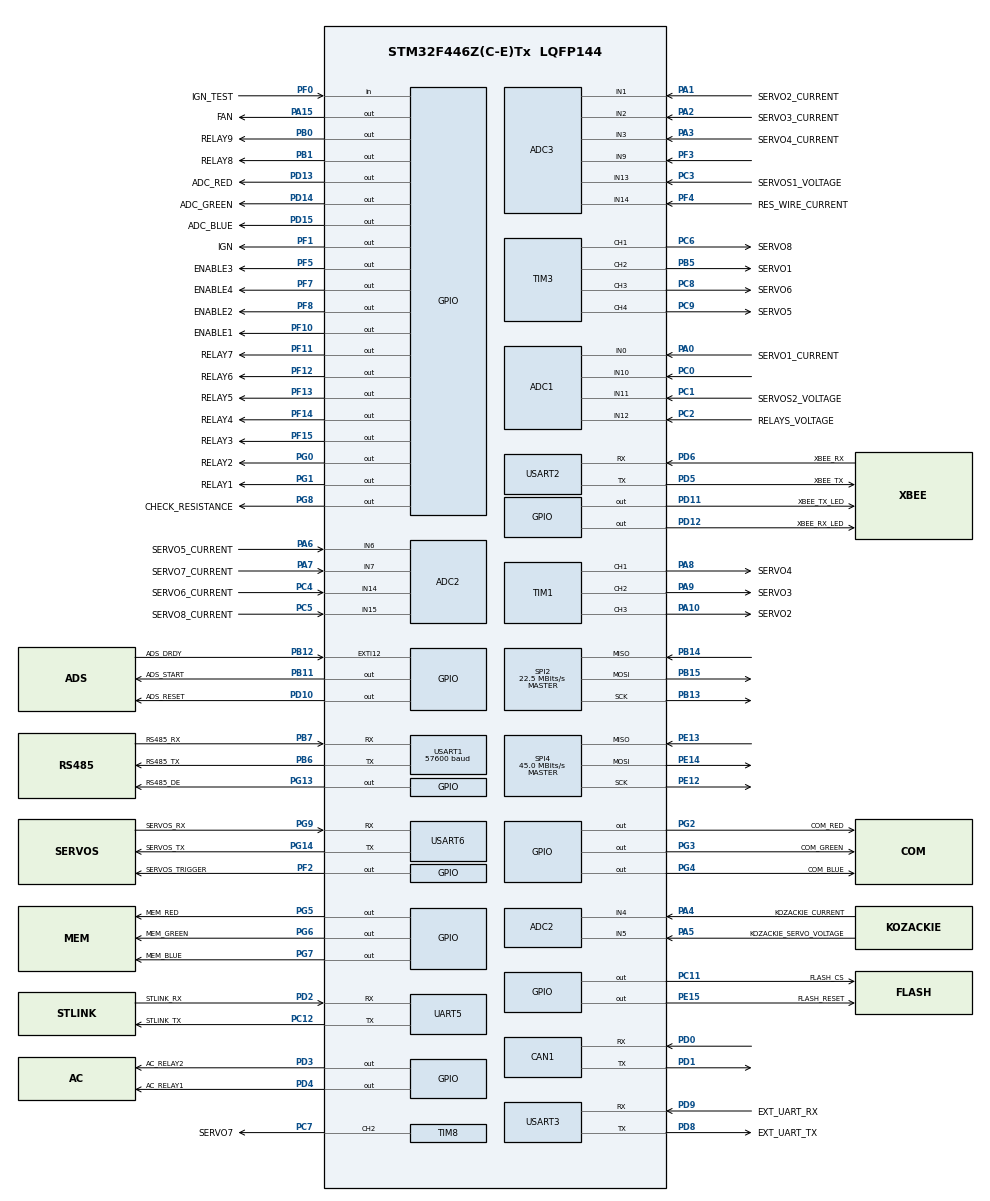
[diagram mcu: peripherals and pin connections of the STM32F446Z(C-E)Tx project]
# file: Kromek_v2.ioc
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ADC1.Channel-0\#ChannelRegularConversion=ADC_CHANNEL_VREFINT
ADC1.Channel-1\#ChannelRegularConversion=ADC_CHANNEL_10
ADC1.Channel-14\#ChannelRegularConversion=ADC_CHANNEL_12
ADC1.Channel-15\#ChannelRegularConversion=ADC_CHANNEL_0
ADC1.Channel-16\#ChannelRegularConversion=ADC_CHANNEL_TEMPSENSOR
ADC1.Channel-2\#ChannelRegularConversion=ADC_CHANNEL_11
ADC1.ClockPrescaler=ADC_CLOCK_SYNC_PCLK_DIV8
ADC1.ContinuousConvMode=ENABLE
ADC1.DMAContinuousRequests=ENABLE
ADC1.DiscontinuousConvMode=DISABLE
ADC1.EOCSelection=ADC_EOC_SEQ_CONV
ADC1.ExternalTrigConv=ADC_SOFTWARE_START
ADC1.InjNumberOfConversion=0
ADC1.NbrOfConversion=6
ADC1.NbrOfConversionFlag=1
ADC1.Rank-0\#ChannelRegularConversion=1
ADC1.Rank-1\#ChannelRegularConversion=2
ADC1.Rank-14\#ChannelRegularConversion=4
ADC1.Rank-15\#ChannelRegularConversion=5
ADC1.Rank-16\#ChannelRegularConversion=6
ADC1.Rank-2\#ChannelRegularConversion=3
ADC1.SamplingTime-0\#ChannelRegularConversion=ADC_SAMPLETIME_480CYCLES
ADC1.SamplingTime-1\#ChannelRegularConversion=ADC_SAMPLETIME_480CYCLES
ADC1.SamplingTime-14\#ChannelRegularConversion=ADC_SAMPLETIME_480CYCLES
ADC1.SamplingTime-15\#ChannelRegularConversion=ADC_SAMPLETIME_480CYCLES
ADC1.SamplingTime-16\#ChannelRegularConversion=ADC_SAMPLETIME_480CYCLES
ADC1.SamplingTime-2\#ChannelRegularConversion=ADC_SAMPLETIME_480CYCLES
ADC1.ScanConvMode=ENABLE
ADC1.master=1
ADC2.Channel-1\#ChannelRegularConversion=ADC_CHANNEL_4
ADC2.Channel-2\#ChannelRegularConversion=ADC_CHANNEL_5
ADC2.Channel-3\#ChannelRegularConversion=ADC_CHANNEL_6
ADC2.Channel-4\#ChannelRegularConversion=ADC_CHANNEL_7
ADC2.Channel-5\#ChannelRegularConversion=ADC_CHANNEL_14
ADC2.Channel-6\#ChannelRegularConversion=ADC_CHANNEL_15
ADC2.ClockPrescaler=ADC_CLOCK_SYNC_PCLK_DIV8
ADC2.ContinuousConvMode=ENABLE
ADC2.DMAContinuousRequests=ENABLE
ADC2.EOCSelection=ADC_EOC_SEQ_CONV
ADC2.NbrOfConversion=6
ADC2.NbrOfConversionFlag=1
ADC2.Rank-1\#ChannelRegularConversion=1
ADC2.Rank-2\#ChannelRegularConversion=2
ADC2.Rank-3\#ChannelRegularConversion=3
ADC2.Rank-4\#ChannelRegularConversion=4
ADC2.Rank-5\#ChannelRegularConversion=5
ADC2.Rank-6\#ChannelRegularConversion=6
ADC2.SamplingTime-1\#ChannelRegularConversion=ADC_SAMPLETIME_480CYCLES
ADC2.SamplingTime-2\#ChannelRegularConversion=ADC_SAMPLETIME_480CYCLES
ADC2.SamplingTime-3\#ChannelRegularConversion=ADC_SAMPLETIME_480CYCLES
ADC2.SamplingTime-4\#ChannelRegularConversion=ADC_SAMPLETIME_480CYCLES
ADC2.SamplingTime-5\#ChannelRegularConversion=ADC_SAMPLETIME_480CYCLES
ADC2.SamplingTime-6\#ChannelRegularConversion=ADC_SAMPLETIME_480CYCLES
ADC2.ScanConvMode=ENABLE
ADC3.Channel-1\#ChannelRegularConversion=ADC_CHANNEL_1
ADC3.Channel-2\#ChannelRegularConversion=ADC_CHANNEL_2
ADC3.Channel-3\#ChannelRegularConversion=ADC_CHANNEL_3
ADC3.Channel-4\#ChannelRegularConversion=ADC_CHANNEL_9
ADC3.Channel-5\#ChannelRegularConversion=ADC_CHANNEL_13
ADC3.Channel-7\#ChannelRegularConversion=ADC_CHANNEL_14
ADC3.ClockPrescaler=ADC_CLOCK_SYNC_PCLK_DIV8
ADC3.ContinuousConvMode=ENABLE
ADC3.DMAContinuousRequests=ENABLE
ADC3.EOCSelection=ADC_EOC_SEQ_CONV
ADC3.NbrOfConversion=6
ADC3.NbrOfConversionFlag=1
ADC3.Rank-1\#ChannelRegularConversion=1
ADC3.Rank-2\#ChannelRegularConversion=2
ADC3.Rank-3\#ChannelRegularConversion=3
ADC3.Rank-4\#ChannelRegularConversion=4
ADC3.Rank-5\#ChannelRegularConversion=5
ADC3.Rank-7\#ChannelRegularConversion=6
ADC3.SamplingTime-1\#ChannelRegularConversion=ADC_SAMPLETIME_480CYCLES
ADC3.SamplingTime-2\#ChannelRegularConversion=ADC_SAMPLETIME_480CYCLES
ADC3.SamplingTime-3\#ChannelRegularConversion=ADC_SAMPLETIME_480CYCLES
ADC3.SamplingTime-4\#ChannelRegularConversion=ADC_SAMPLETIME_480CYCLES
ADC3.SamplingTime-5\#ChannelRegularConversion=ADC_SAMPLETIME_480CYCLES
ADC3.SamplingTime-7\#ChannelRegularConversion=ADC_SAMPLETIME_480CYCLES
ADC3.ScanConvMode=ENABLE
CAN1.BS1=CAN_BS1_1TQ
CAN1.BS2=CAN_BS2_1TQ
CAN1.CalculateTimeQuantum=355.55555555555554
Dma.ADC1.0.Direction=DMA_PERIPH_TO_MEMORY
Dma.ADC1.0.FIFOMode=DMA_FIFOMODE_DISABLE
Dma.ADC1.0.Instance=DMA2_Stream4
Dma.ADC1.0.MemDataAlignment=DMA_MDATAALIGN_HALFWORD
Dma.ADC1.0.MemInc=DMA_MINC_ENABLE
Dma.ADC1.0.Mode=DMA_CIRCULAR
Dma.ADC1.0.PeriphDataAlignment=DMA_PDATAALIGN_HALFWORD
Dma.ADC1.0.PeriphInc=DMA_PINC_DISABLE
Dma.ADC1.0.Priority=DMA_PRIORITY_LOW
Dma.ADC2.1.Direction=DMA_PERIPH_TO_MEMORY
Dma.ADC2.1.FIFOMode=DMA_FIFOMODE_DISABLE
Dma.ADC2.1.Instance=DMA2_Stream2
Dma.ADC2.1.MemDataAlignment=DMA_MDATAALIGN_HALFWORD
Dma.ADC2.1.MemInc=DMA_MINC_ENABLE
Dma.ADC2.1.Mode=DMA_CIRCULAR
Dma.ADC2.1.PeriphDataAlignment=DMA_PDATAALIGN_HALFWORD
Dma.ADC2.1.PeriphInc=DMA_PINC_DISABLE
Dma.ADC2.1.Priority=DMA_PRIORITY_LOW
Dma.ADC3.2.Direction=DMA_PERIPH_TO_MEMORY
Dma.ADC3.2.FIFOMode=DMA_FIFOMODE_DISABLE
Dma.ADC3.2.Instance=DMA2_Stream0
Dma.ADC3.2.MemDataAlignment=DMA_MDATAALIGN_HALFWORD
Dma.ADC3.2.MemInc=DMA_MINC_ENABLE
Dma.ADC3.2.Mode=DMA_CIRCULAR
Dma.ADC3.2.PeriphDataAlignment=DMA_PDATAALIGN_HALFWORD
Dma.ADC3.2.PeriphInc=DMA_PINC_DISABLE
Dma.ADC3.2.Priority=DMA_PRIORITY_LOW
Dma.Request0=ADC1
Dma.Request1=ADC2
Dma.Request10=USART2_TX
Dma.Request2=ADC3
Dma.Request3=SPI2_RX
Dma.Request4=SPI2_TX
Dma.Request5=SPI4_RX
Dma.Request6=SPI4_TX
Dma.Request7=USART1_RX
Dma.Request8=USART1_TX
Dma.Request9=USART2_RX
Dma.SPI2_RX.3.Direction=DMA_PERIPH_TO_MEMORY
Dma.SPI2_RX.3.FIFOMode=DMA_FIFOMODE_DISABLE
Dma.SPI2_RX.3.Instance=DMA1_Stream3
Dma.SPI2_RX.3.MemDataAlignment=DMA_MDATAALIGN_BYTE
Dma.SPI2_RX.3.MemInc=DMA_MINC_ENABLE
Dma.SPI2_RX.3.Mode=DMA_NORMAL
Dma.SPI2_RX.3.PeriphDataAlignment=DMA_PDATAALIGN_BYTE
Dma.SPI2_RX.3.PeriphInc=DMA_PINC_DISABLE
Dma.SPI2_RX.3.Priority=DMA_PRIORITY_LOW
Dma.SPI2_TX.4.Direction=DMA_MEMORY_TO_PERIPH
Dma.SPI2_TX.4.FIFOMode=DMA_FIFOMODE_DISABLE
Dma.SPI2_TX.4.Instance=DMA1_Stream4
Dma.SPI2_TX.4.MemDataAlignment=DMA_MDATAALIGN_BYTE
Dma.SPI2_TX.4.MemInc=DMA_MINC_ENABLE
Dma.SPI2_TX.4.Mode=DMA_NORMAL
Dma.SPI2_TX.4.PeriphDataAlignment=DMA_PDATAALIGN_BYTE
Dma.SPI2_TX.4.PeriphInc=DMA_PINC_DISABLE
Dma.SPI2_TX.4.Priority=DMA_PRIORITY_LOW
Dma.SPI4_RX.5.Direction=DMA_PERIPH_TO_MEMORY
Dma.SPI4_RX.5.FIFOMode=DMA_FIFOMODE_DISABLE
Dma.SPI4_RX.5.Instance=DMA2_Stream3
Dma.SPI4_RX.5.MemDataAlignment=DMA_MDATAALIGN_BYTE
Dma.SPI4_RX.5.MemInc=DMA_MINC_ENABLE
Dma.SPI4_RX.5.Mode=DMA_NORMAL
Dma.SPI4_RX.5.PeriphDataAlignment=DMA_PDATAALIGN_BYTE
Dma.SPI4_RX.5.PeriphInc=DMA_PINC_DISABLE
Dma.SPI4_RX.5.Priority=DMA_PRIORITY_LOW
Dma.SPI4_TX.6.Direction=DMA_MEMORY_TO_PERIPH
Dma.SPI4_TX.6.FIFOMode=DMA_FIFOMODE_DISABLE
Dma.SPI4_TX.6.Instance=DMA2_Stream1
Dma.SPI4_TX.6.MemDataAlignment=DMA_MDATAALIGN_BYTE
Dma.SPI4_TX.6.MemInc=DMA_MINC_ENABLE
Dma.SPI4_TX.6.Mode=DMA_NORMAL
Dma.SPI4_TX.6.PeriphDataAlignment=DMA_PDATAALIGN_BYTE
Dma.SPI4_TX.6.PeriphInc=DMA_PINC_DISABLE
Dma.SPI4_TX.6.Priority=DMA_PRIORITY_LOW
Dma.USART1_RX.7.Direction=DMA_PERIPH_TO_MEMORY
Dma.USART1_RX.7.FIFOMode=DMA_FIFOMODE_DISABLE
Dma.USART1_RX.7.Instance=DMA2_Stream5
Dma.USART1_RX.7.MemDataAlignment=DMA_MDATAALIGN_BYTE
Dma.USART1_RX.7.MemInc=DMA_MINC_ENABLE
Dma.USART1_RX.7.Mode=DMA_NORMAL
Dma.USART1_RX.7.PeriphDataAlignment=DMA_PDATAALIGN_BYTE
Dma.USART1_RX.7.PeriphInc=DMA_PINC_DISABLE
Dma.USART1_RX.7.Priority=DMA_PRIORITY_LOW
Dma.USART1_TX.8.Direction=DMA_MEMORY_TO_PERIPH
Dma.USART1_TX.8.FIFOMode=DMA_FIFOMODE_DISABLE
Dma.USART1_TX.8.Instance=DMA2_Stream7
Dma.USART1_TX.8.MemDataAlignment=DMA_MDATAALIGN_BYTE
Dma.USART1_TX.8.MemInc=DMA_MINC_ENABLE
Dma.USART1_TX.8.Mode=DMA_NORMAL
Dma.USART1_TX.8.PeriphDataAlignment=DMA_PDATAALIGN_BYTE
Dma.USART1_TX.8.PeriphInc=DMA_PINC_DISABLE
Dma.USART1_TX.8.Priority=DMA_PRIORITY_LOW
Dma.USART2_RX.9.Direction=DMA_PERIPH_TO_MEMORY
Dma.USART2_RX.9.FIFOMode=DMA_FIFOMODE_DISABLE
Dma.USART2_RX.9.Instance=DMA1_Stream5
Dma.USART2_RX.9.MemDataAlignment=DMA_MDATAALIGN_BYTE
Dma.USART2_RX.9.MemInc=DMA_MINC_ENABLE
Dma.USART2_RX.9.Mode=DMA_NORMAL
Dma.USART2_RX.9.PeriphDataAlignment=DMA_PDATAALIGN_BYTE
Dma.USART2_RX.9.PeriphInc=DMA_PINC_DISABLE
Dma.USART2_RX.9.Priority=DMA_PRIORITY_LOW
Dma.USART2_TX.10.Direction=DMA_MEMORY_TO_PERIPH
Dma.USART2_TX.10.FIFOMode=DMA_FIFOMODE_DISABLE
Dma.USART2_TX.10.Instance=DMA1_Stream6
Dma.USART2_TX.10.MemDataAlignment=DMA_MDATAALIGN_BYTE
Dma.USART2_TX.10.MemInc=DMA_MINC_ENABLE
Dma.USART2_TX.10.Mode=DMA_NORMAL
Dma.USART2_TX.10.PeriphDataAlignment=DMA_PDATAALIGN_BYTE
Dma.USART2_TX.10.PeriphInc=DMA_PINC_DISABLE
Dma.USART2_TX.10.Priority=DMA_PRIORITY_LOW
Mcu.Family=STM32F4
Mcu.Name=STM32F446Z(C-E)Tx
Mcu.Package=LQFP144
NVIC.ADC_IRQn=true\:0\:0\:false\:false\:true\:true\:true
NVIC.DMA1_Stream3_IRQn=true\:0\:0\:false\:false\:true\:false\:true
NVIC.DMA1_Stream4_IRQn=true\:0\:0\:false\:false\:true\:false\:true
NVIC.DMA1_Stream5_IRQn=true\:0\:0\:false\:false\:true\:false\:true
NVIC.DMA1_Stream6_IRQn=true\:0\:0\:false\:false\:true\:false\:true
NVIC.DMA2_Stream0_IRQn=true\:0\:0\:false\:false\:true\:false\:true
NVIC.DMA2_Stream1_IRQn=true\:0\:0\:false\:false\:true\:false\:true
NVIC.DMA2_Stream2_IRQn=true\:0\:0\:false\:false\:true\:false\:true
NVIC.DMA2_Stream3_IRQn=true\:0\:0\:false\:false\:true\:false\:true
NVIC.DMA2_Stream4_IRQn=true\:0\:0\:false\:false\:true\:false\:true
NVIC.DMA2_Stream5_IRQn=true\:0\:0\:true\:false\:true\:false\:true
NVIC.DMA2_Stream7_IRQn=true\:0\:0\:true\:false\:true\:false\:true
NVIC.EXTI15_10_IRQn=true\:0\:0\:false\:false\:true\:true\:true
NVIC.PriorityGroup=NVIC_PRIORITYGROUP_4
NVIC.SPI2_IRQn=true\:0\:0\:false\:false\:true\:true\:true
NVIC.SPI4_IRQn=true\:0\:0\:false\:false\:true\:true\:true
NVIC.TIM8_TRG_COM_TIM14_IRQn=true\:1\:0\:true\:false\:true\:true\:true
NVIC.TIM8_UP_TIM13_IRQn=true\:2\:0\:true\:false\:true\:true\:true
NVIC.USART1_IRQn=true\:0\:0\:true\:false\:true\:true\:true
NVIC.USART2_IRQn=true\:0\:0\:false\:false\:true\:true\:true
NVIC.USART3_IRQn=true\:0\:0\:false\:false\:true\:true\:true
PA0-WKUP.GPIO_Label=SERVO1_CURRENT
PA0-WKUP.Signal=ADCx_IN0
PA1.GPIO_Label=SERVO2_CURRENT
PA1.Signal=ADCx_IN1
PA10.GPIO_Label=SERVO2
PA10.Signal=S_TIM1_CH3
PA13.Mode=Serial_Wire
PA13.Signal=SYS_JTMS-SWDIO
PA14.Mode=Serial_Wire
PA14.Signal=SYS_JTCK-SWCLK
PA15.GPIO_Label=FAN
PA15.Signal=GPIO_Output
PA2.GPIO_Label=SERVO3_CURRENT
PA2.Signal=ADCx_IN2
PA3.GPIO_Label=SERVO4_CURRENT
PA3.Signal=ADCx_IN3
PA4.GPIO_Label=KOZACKIE_CURRENT
PA4.Signal=ADCx_IN4
PA5.GPIO_Label=KOZACKIE_SERVO_VOLTAGE
PA5.Signal=ADCx_IN5
PA6.GPIO_Label=SERVO5_CURRENT
PA6.Signal=ADCx_IN6
PA7.GPIO_Label=SERVO7_CURRENT
PA7.Signal=ADCx_IN7
PA8.GPIO_Label=SERVO4
PA8.Signal=S_TIM1_CH1
PA9.GPIO_Label=SERVO3
PA9.Signal=S_TIM1_CH2
PB0.GPIO_Label=RELAY9
PB0.Signal=GPIO_Output
PB1.GPIO_Label=RELAY8
PB1.Signal=GPIO_Output
PB11.GPIO_Label=ADS_START
PB11.Signal=GPIO_Output
PB12.GPIO_Label=ADS_DRDY
PB12.Signal=GPXTI12
PB13.Mode=Full_Duplex_Master
PB13.Signal=SPI2_SCK
PB14.Mode=Full_Duplex_Master
PB14.Signal=SPI2_MISO
PB15.Mode=Full_Duplex_Master
PB15.Signal=SPI2_MOSI
PB2.Signal=QUADSPI_CLK
PB3.Signal=I2C2_SDA
PB4.Signal=I2C3_SDA
PB5.GPIO_Label=SERVO1
PB5.Signal=S_TIM3_CH2
PB6.GPIO_Label=RS485_TX
PB6.Mode=Asynchronous
PB6.Signal=USART1_TX
PB7.GPIO_Label=RS485_RX
PB7.Mode=Asynchronous
PB7.Signal=USART1_RX
PB8.Signal=I2C1_SCL
PB9.Signal=I2C1_SDA
PC0.Signal=ADCx_IN10
PC1.GPIO_Label=SERVOS2_VOLTAGE
PC1.Signal=ADCx_IN11
PC11.GPIO_Label=FLASH_CS
PC11.Signal=GPIO_Output
PC12.GPIO_Label=STLINK_TX
PC12.Mode=Asynchronous
PC12.Signal=UART5_TX
PC15-OSC32_OUT.Signal=RCC_OSC32_OUT
PC2.GPIO_Label=RELAYS_VOLTAGE
PC2.Signal=ADCx_IN12
PC3.GPIO_Label=SERVOS1_VOLTAGE
PC3.Signal=ADCx_IN13
PC4.GPIO_Label=SERVO6_CURRENT
PC4.Signal=ADCx_IN14
PC5.GPIO_Label=SERVO8_CURRENT
PC5.Signal=ADCx_IN15
PC6.GPIO_Label=SERVO8
PC6.Signal=S_TIM3_CH1
PC7.GPIO_Label=SERVO7
PC7.Signal=S_TIM8_CH2
PC8.GPIO_Label=SERVO6
PC8.Signal=S_TIM3_CH3
PC9.GPIO_Label=SERVO5
PC9.Signal=S_TIM3_CH4
PD0.Mode=Master
PD0.Signal=CAN1_RX
PD1.Mode=Master
PD1.Signal=CAN1_TX
PD10.GPIO_Label=ADS_RESET
PD10.Signal=GPIO_Output
PD11.GPIO_Label=XBEE_TX_LED
PD11.Signal=GPIO_Output
PD12.GPIO_Label=XBEE_RX_LED
PD12.Signal=GPIO_Output
PD13.GPIO_Label=ADC_RED
PD13.Signal=GPIO_Output
PD14.GPIO_Label=ADC_GREEN
PD14.Signal=GPIO_Output
PD15.GPIO_Label=ADC_BLUE
PD15.Signal=GPIO_Output
PD2.GPIO_Label=STLINK_RX
PD2.Mode=Asynchronous
PD2.Signal=UART5_RX
PD3.GPIO_Label=AC_RELAY2
PD3.Signal=GPIO_Output
PD4.GPIO_Label=AC_RELAY1
PD4.Signal=GPIO_Output
PD5.GPIO_Label=XBEE_TX
PD5.Mode=Asynchronous
PD5.Signal=USART2_TX
PD6.GPIO_Label=XBEE_RX
PD6.Mode=Asynchronous
PD6.Signal=USART2_RX
PD8.GPIO_Label=EXT_UART_TX
PD8.Mode=Asynchronous
PD8.Signal=USART3_TX
PD9.GPIO_Label=EXT_UART_RX
PD9.Mode=Asynchronous
PD9.Signal=USART3_RX
PE10.Signal=QUADSPI_BK2_IO3
PE12.Mode=Full_Duplex_Master
PE12.Signal=SPI4_SCK
PE13.Mode=Full_Duplex_Master
PE13.Signal=SPI4_MISO
PE14.Mode=Full_Duplex_Master
PE14.Signal=SPI4_MOSI
PE15.GPIO_Label=FLASH_RESET
PE15.Signal=GPIO_Output
PE7.Signal=QUADSPI_BK2_IO0
PE8.Signal=QUADSPI_BK2_IO1
PE9.Signal=QUADSPI_BK2_IO2
PF0.GPIO_Label=IGN_TEST
PF0.Signal=GPIO_Input
PF1.GPIO_Label=IGN
PF1.Signal=GPIO_Output
PF10.GPIO_Label=ENABLE1
PF10.Signal=GPIO_Output
PF11.GPIO_Label=RELAY7
PF11.Signal=GPIO_Output
PF12.GPIO_Label=RELAY6
PF12.Signal=GPIO_Output
PF13.GPIO_Label=RELAY5
PF13.Signal=GPIO_Output
PF14.GPIO_Label=RELAY4
PF14.Signal=GPIO_Output
PF15.GPIO_Label=RELAY3
PF15.Signal=GPIO_Output
PF2.GPIO_Label=SERVOS_TRIGGER
PF2.Signal=GPIO_Output
PF3.Mode=IN9
PF3.Signal=ADC3_IN9
PF4.GPIO_Label=RES_WIRE_CURRENT
PF4.Mode=IN14
PF4.Signal=ADC3_IN14
PF5.GPIO_Label=ENABLE3
PF5.Signal=GPIO_Output
PF7.GPIO_Label=ENABLE4
PF7.Signal=GPIO_Output
PF8.GPIO_Label=ENABLE2
PF8.Signal=GPIO_Output
PF9.GPIO_Label=BUZZER
PF9.Signal=S_TIM14_CH1
PG0.GPIO_Label=RELAY2
PG0.Signal=GPIO_Output
PG1.GPIO_Label=RELAY1
PG1.Signal=GPIO_Output
PG13.GPIO_Label=RS485_DE
PG13.Signal=GPIO_Output
PG14.GPIO_Label=SERVOS_TX
PG14.Mode=Asynchronous
PG14.Signal=USART6_TX
PG2.GPIO_Label=COM_RED
PG2.Signal=GPIO_Output
PG3.GPIO_Label=COM_GREEN
PG3.Signal=GPIO_Output
PG4.GPIO_Label=COM_BLUE
PG4.Signal=GPIO_Output
PG5.GPIO_Label=MEM_RED
PG5.Signal=GPIO_Output
PG6.GPIO_Label=MEM_GREEN
PG6.Signal=GPIO_Output
PG7.GPIO_Label=MEM_BLUE
PG7.Signal=GPIO_Output
PG8.GPIO_Label=CHECK_RESISTANCE
PG8.Signal=GPIO_Output
PG9.GPIO_Label=SERVOS_RX
PG9.Mode=Asynchronous
PG9.Signal=USART6_RX
PH0-OSC_IN.Signal=RCC_OSC_IN
PH1-OSC_OUT.Signal=RCC_OSC_OUT
ProjectManager.HeapSize=0x200
ProjectManager.StackSize=0x400
ProjectManager.TargetToolchain=SW4STM32
RCC.AHBFreq_Value=180000000
RCC.APB1CLKDivider=RCC_HCLK_DIV4
RCC.APB1Freq_Value=45000000
RCC.APB1TimFreq_Value=90000000
RCC.APB2CLKDivider=RCC_HCLK_DIV2
RCC.APB2Freq_Value=90000000
RCC.APB2TimFreq_Value=180000000
RCC.CortexFreq_Value=180000000
RCC.HCLKFreq_Value=180000000
RCC.HSE_VALUE=8000000
RCC.PLLM=8
RCC.PLLN=180
RCC.PLLQ=8
RCC.PLLSAIM=8
RCC.PLLSAIN=96
RCC.PLLSAIP=RCC_PLLSAIP_DIV4
RCC.SYSCLKFreq_VALUE=180000000
RCC.SYSCLKSource=RCC_SYSCLKSOURCE_PLLRCLK
RCC.USBCLockSelection=RCC_CLK48CLKSOURCE_PLLSAIP
RCC.USBFreq_Value=48000000
RCC.VCOOutputFreq_Value=360000000
SH.ADCx_IN0.0=ADC1_IN0,IN0
SH.ADCx_IN1.0=ADC3_IN1,IN1
SH.ADCx_IN10.0=ADC1_IN10,IN10
SH.ADCx_IN11.0=ADC1_IN11,IN11
SH.ADCx_IN12.0=ADC1_IN12,IN12
SH.ADCx_IN13.0=ADC3_IN13,IN13
SH.ADCx_IN14.0=ADC2_IN14,IN14
SH.ADCx_IN15.0=ADC2_IN15,IN15
SH.ADCx_IN2.0=ADC3_IN2,IN2
SH.ADCx_IN3.0=ADC3_IN3,IN3
SH.ADCx_IN4.0=ADC2_IN4,IN4
SH.ADCx_IN5.0=ADC2_IN5,IN5
SH.ADCx_IN6.0=ADC2_IN6,IN6
SH.ADCx_IN7.0=ADC2_IN7,IN7
SH.S_TIM14_CH1.0=TIM14_CH1
SH.S_TIM1_CH1.0=TIM1_CH1,PWM Generation1 CH1
SH.S_TIM1_CH2.0=TIM1_CH2,PWM Generation2 CH2
SH.S_TIM1_CH3.0=TIM1_CH3,PWM Generation3 CH3
SH.S_TIM3_CH1.0=TIM3_CH1,PWM Generation1 CH1
SH.S_TIM3_CH2.0=TIM3_CH2,PWM Generation2 CH2
SH.S_TIM3_CH3.0=TIM3_CH3,PWM Generation3 CH3
SH.S_TIM3_CH4.0=TIM3_CH4,PWM Generation4 CH4
SH.S_TIM8_CH2.0=TIM8_CH2,PWM Generation2 CH2
SPI2.BaudRatePrescaler=SPI_BAUDRATEPRESCALER_2
SPI2.CalculateBaudRate=22.5 MBits/s
SPI2.Direction=SPI_DIRECTION_2LINES
SPI2.Mode=SPI_MODE_MASTER
SPI2.VirtualType=VM_MASTER
SPI4.CalculateBaudRate=45.0 MBits/s
SPI4.Direction=SPI_DIRECTION_2LINES
SPI4.Mode=SPI_MODE_MASTER
SPI4.VirtualType=VM_MASTER
TIM1.Channel-PWM\ Generation1\ CH1=TIM_CHANNEL_1
TIM1.Channel-PWM\ Generation2\ CH2=TIM_CHANNEL_2
TIM1.Channel-PWM\ Generation3\ CH3=TIM_CHANNEL_3
TIM1.TIM_MasterOutputTrigger=TIM_TRGO_RESET
TIM13.Period=9
TIM13.Prescaler=39
TIM14.Period=9
TIM14.Prescaler=39
TIM3.Channel-PWM\ Generation1\ CH1=TIM_CHANNEL_1
TIM3.Channel-PWM\ Generation2\ CH2=TIM_CHANNEL_2
TIM3.Channel-PWM\ Generation3\ CH3=TIM_CHANNEL_3
TIM3.Channel-PWM\ Generation4\ CH4=TIM_CHANNEL_4
TIM8.Channel-PWM\ Generation2\ CH2=TIM_CHANNEL_2
TIM8.Period=0
TIM8.Prescaler=0
TIM8.TIM_MasterOutputTrigger=TIM_TRGO_UPDATE
UART5.VirtualMode=Asynchronous
USART1.BaudRate=57600
USART1.VirtualMode=VM_ASYNC
USART2.VirtualMode=VM_ASYNC
USART3.VirtualMode=VM_ASYNC
USART6.VirtualMode=VM_ASYNC
VP_ADC1_TempSens_Input.Mode=IN-TempSens
VP_ADC1_Vref_Input.Mode=IN-Vrefint
VP_CRC_VS_CRC.Mode=CRC_Activate
VP_TIM13_VS_ClockSourceINT.Mode=Enable_Timer
VP_TIM14_VS_ClockSourceINT.Mode=Enable_Timer
board=custom

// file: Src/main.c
/* USER CODE BEGIN Header */
/**
  ******************************************************************************
  * @file           : main.c
  * @brief          : Main program body
  ******************************************************************************
  * @attention
  *
  * <h2><center>&copy; Copyright (c) 2019 STMicroelectronics.
  * All rights reserved.</center></h2>
  *
  * This software component is licensed by ST under BSD 3-Clause license,
  * the "License"; You may not use this file except in compliance with the
  * License. You may obtain a copy of the License at:
  *                        opensource.org/licenses/BSD-3-Clause
  *
  ******************************************************************************
  */
/* USER CODE END Header */

#include "main.h"
#include "adc.h"
#include "can.h"
#include "crc.h"
#include "dma.h"
#include "spi.h"
#include "tim.h"
#include "usart.h"
#include "gpio.h"

/* USER CODE BEGIN Includes */
#include "stdio.h"
#include "SS_Kromek_adc.h"
#include "SS_supply_control.h"
#include "SS_Kromek_tests.h"
#include "SS_servos.h"
#include "SS_relays.h"
#include "SS_dynamixel.h"
#include "SS_Grazyna_com.h"
#include "SS_settings.h"
#include "SS_ADS1258.h"
/* USER CODE END Includes */

void SystemClock_Config(void);

int main(void)
{

  /* MCU Configuration--------------------------------------------------------*/

  /* Reset of all peripherals, Initializes the Flash interface and the Systick. */
  HAL_Init();

  /* Configure the system clock */
  SystemClock_Config();

  /* Initialize all configured peripherals */
  MX_GPIO_Init();
  MX_UART5_Init();
  MX_USART6_UART_Init();
  MX_DMA_Init();
  MX_SPI2_Init();
  MX_SPI4_Init();
  MX_USART1_UART_Init();
  MX_USART3_UART_Init();
  MX_TIM13_Init();
  MX_TIM14_Init();
  /* USER CODE BEGIN 2 */

  /* STM32 CubeMX v5.4.0 bug - MX functions using DMA need to be initialized after calling MX_DMA_Init() */
  MX_ADC1_Init();
  MX_ADC2_Init();
  MX_ADC3_Init();
  MX_USART2_UART_Init();

#ifndef SIMULATE
  MX_CAN1_Init();
  MX_TIM1_Init();
  MX_TIM3_Init();
  MX_TIM8_Init();
  MX_CRC_Init();
#endif

#ifdef RUN_TESTS
  SS_Kromek_run_all_tests();
#endif

//  SS_supply_init();
//  SS_adc_init();
//  SS_servos_init();
  SS_grazyna_init();
//  SS_measurements_init();
  printf("Elon!\r\n");
//  SS_settings_read_json(settings_json);
  /* USER CODE END 2 */

  /* Infinite loop */
  /* USER CODE BEGIN WHILE */
  while (1)
  {
      SS_grazyna_main();
    /* USER CODE END WHILE */

  }
}

void SystemClock_Config(void)
{
  RCC_OscInitTypeDef RCC_OscInitStruct = {0};
  RCC_ClkInitTypeDef RCC_ClkInitStruct = {0};

  /** Configure the main internal regulator output voltage
  */
  __HAL_RCC_PWR_CLK_ENABLE();
  __HAL_PWR_VOLTAGESCALING_CONFIG(PWR_REGULATOR_VOLTAGE_SCALE1);
  /** Initializes the CPU, AHB and APB busses clocks
  */
  RCC_OscInitStruct.OscillatorType = RCC_OSCILLATORTYPE_HSI;
  RCC_OscInitStruct.HSIState = RCC_HSI_ON;
  RCC_OscInitStruct.HSICalibrationValue = RCC_HSICALIBRATION_DEFAULT;
  RCC_OscInitStruct.PLL.PLLState = RCC_PLL_ON;
  RCC_OscInitStruct.PLL.PLLSource = RCC_PLLSOURCE_HSI;
  RCC_OscInitStruct.PLL.PLLM = 8;
  RCC_OscInitStruct.PLL.PLLN = 180;
  RCC_OscInitStruct.PLL.PLLP = RCC_PLLP_DIV2;
  RCC_OscInitStruct.PLL.PLLQ = 2;
  RCC_OscInitStruct.PLL.PLLR = 2;
  if (HAL_RCC_OscConfig(&RCC_OscInitStruct) != HAL_OK)
  {
    Error_Handler();
  }
  /** Activate the Over-Drive mode
  */
  if (HAL_PWREx_EnableOverDrive() != HAL_OK)
  {
    Error_Handler();
  }
  /** Initializes the CPU, AHB and APB busses clocks
  */
  RCC_ClkInitStruct.ClockType = RCC_CLOCKTYPE_HCLK|RCC_CLOCKTYPE_SYSCLK
                              |RCC_CLOCKTYPE_PCLK1|RCC_CLOCKTYPE_PCLK2;
  RCC_ClkInitStruct.SYSCLKSource = RCC_SYSCLKSOURCE_PLLCLK;
  RCC_ClkInitStruct.AHBCLKDivider = RCC_SYSCLK_DIV1;
  RCC_ClkInitStruct.APB1CLKDivider = RCC_HCLK_DIV4;
  RCC_ClkInitStruct.APB2CLKDivider = RCC_HCLK_DIV2;

  if (HAL_RCC_ClockConfig(&RCC_ClkInitStruct, FLASH_LATENCY_5) != HAL_OK)
  {
    Error_Handler();
  }
}

void Error_Handler(void)
{
  /* USER CODE BEGIN Error_Handler_Debug */
  /* User can add his own implementation to report the HAL error return state */
    printf("HAL Error\r\n");
  /* USER CODE END Error_Handler_Debug */
}

/************************ (C) COPYRIGHT STMicroelectronics *****END OF FILE****/
